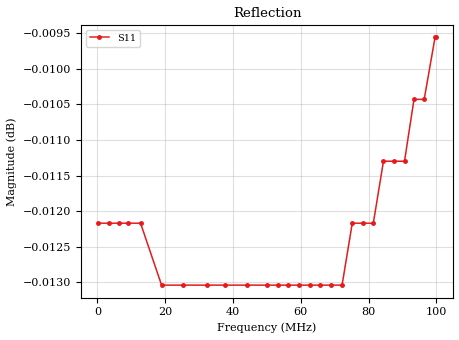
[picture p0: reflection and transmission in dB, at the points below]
! ListType=Lin
!!SAA-2 male short 0.1 to 100MHz 500 points
# MHz S RI R 50
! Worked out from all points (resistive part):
!   500 points, 100 kHz to 100 MHz, reference 50 ohm
!   read as one part to ground: R = 36.1 mohm at 500.4 kHz
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0.1  -0.9986 -0.000144
3.303206  -0.9986 -0.000146
6.306212  -0.9986 -0.000145
8.908818  -0.9986 -0.000142
12.71263  -0.9986 -0.000134
18.91884  -0.9985 -0.000121
25.12505  -0.9985 -0.000105
32.33226  -0.9985 -8.43e-05
37.73768  -0.9985 -6.7e-05
44.14409  -0.9985 -4.44e-05
50.1501  -0.9985 -2.14e-05
53.35331  -0.9985 -7.6e-06
56.35631  -0.9985 7e-06
59.35932  -0.9985 2.31e-05
62.56253  -0.9985 4.22e-05
65.56553  -0.9985 6.17e-05
68.76874  -0.9985 8.43e-05
72.17214  -0.9985 0.00011
75.17515  -0.9986 0.000135
78.37836  -0.9986 0.000163
81.38136  -0.9986 0.000191
84.38437  -0.9987 0.000221
87.58758  -0.9987 0.000254
90.59058  -0.9987 0.000287
93.39339  -0.9988 0.000319
96.39639  -0.9988 0.000355
99.5996  -0.9989 0.000395
100  -0.9989 0.0004
